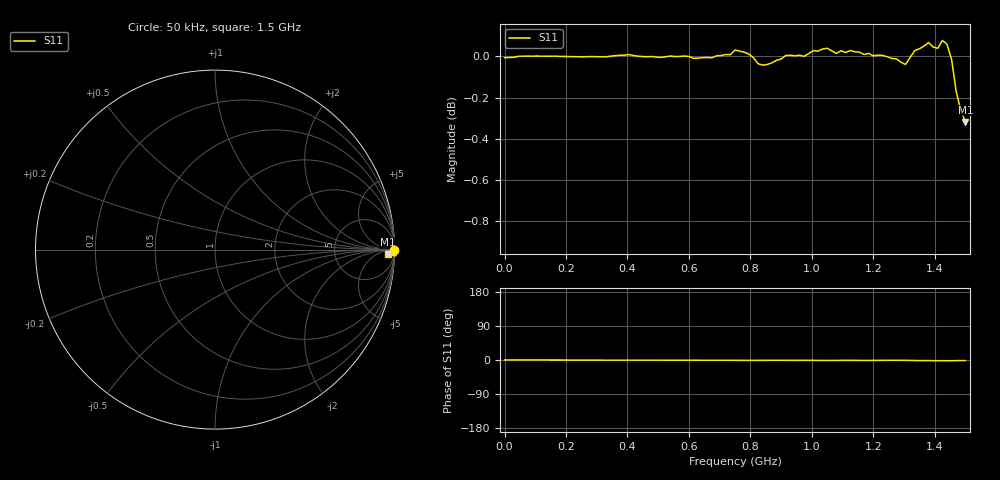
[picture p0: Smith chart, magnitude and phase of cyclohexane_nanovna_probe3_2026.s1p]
! Touchstone S1P file exported from NanoVNA UTN Toolkit
! Device: NanoVNA-H
! Export date: 2026-10-13 12:03:41
! Frequency range: 0.050 - 1500.000 MHz
! Number of points: 101
! Parameter: S11 (Reflection)
# Hz S RI R 50
! f[Hz]  S11_real S11_imag
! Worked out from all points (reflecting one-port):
!   101 points, 50 kHz to 1.5 GHz, reference 50 ohm
!   lowest |S11| = -0.3 dB at 1.5 GHz (marker M1), VSWR 54.55, Z = 1.78e+03 - j1.3e+03 ohm
!   phase of S11 starts at -0 deg and turns -1 deg over the sweep
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50000  0.9994 -0.000847
1.950435e8  1 -0.00346
3.750375e8  1.001 -0.00679
5.70031e8  1 -0.0107
6.750275e8  0.9992 -0.0131
7.50025e8  1.004 -0.0155
7.950235e8  1.001 -0.0177
8.40022e8  0.995 -0.0156
9.450185e8  1 -0.0145
9.90017e8  1.002 -0.0143
1.065014e9  1.003 -0.0208
1.095014e9  1.003 -0.0156
1.140012e9  1.003 -0.016
1.170011e9  1.001 -0.0201
1.21501e9  1.001 -0.0184
1.245008e9  0.9998 -0.0134
1.290007e9  0.9967 -0.0137
1.305006e9  0.9954 -0.0155
1.320006e9  0.9993 -0.0184
1.335006e9  1.003 -0.0232
1.380004e9  1.008 -0.0246
1.395004e9  1.005 -0.0322
1.410003e9  1.004 -0.0333
1.425002e9  1.008 -0.0321
1.440002e9  1.006 -0.0329
1.455002e9  0.9977 -0.0357
1.470001e9  0.9803 -0.0259
1.5e9  0.9637 -0.0258
